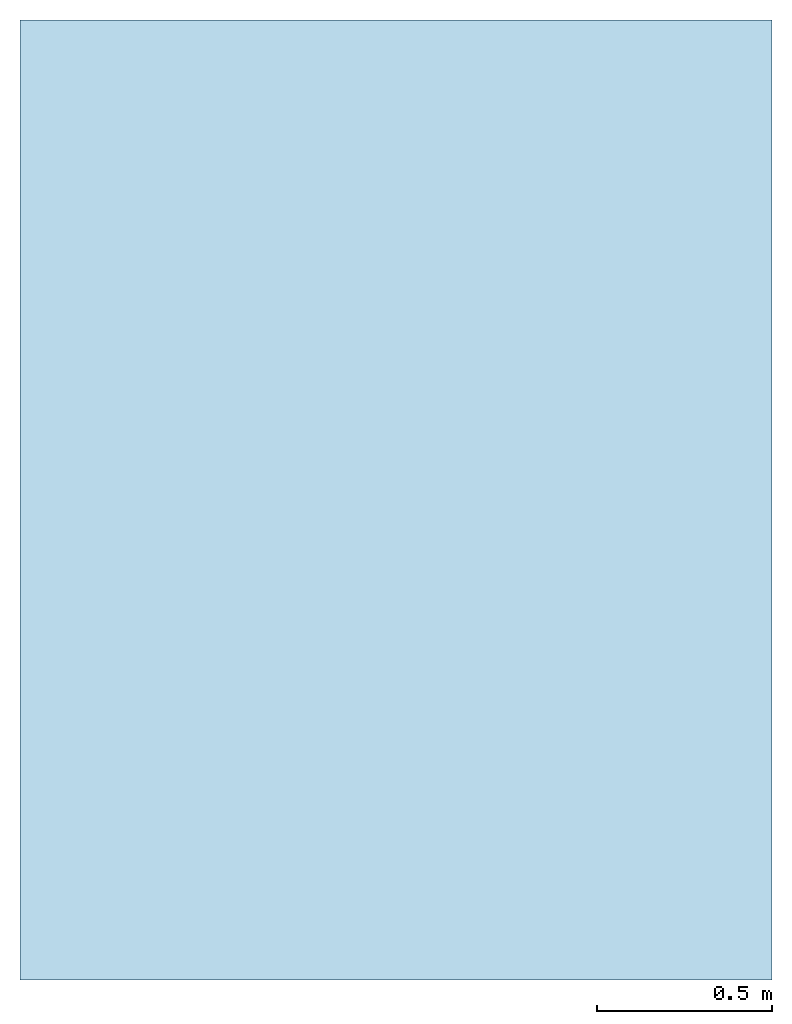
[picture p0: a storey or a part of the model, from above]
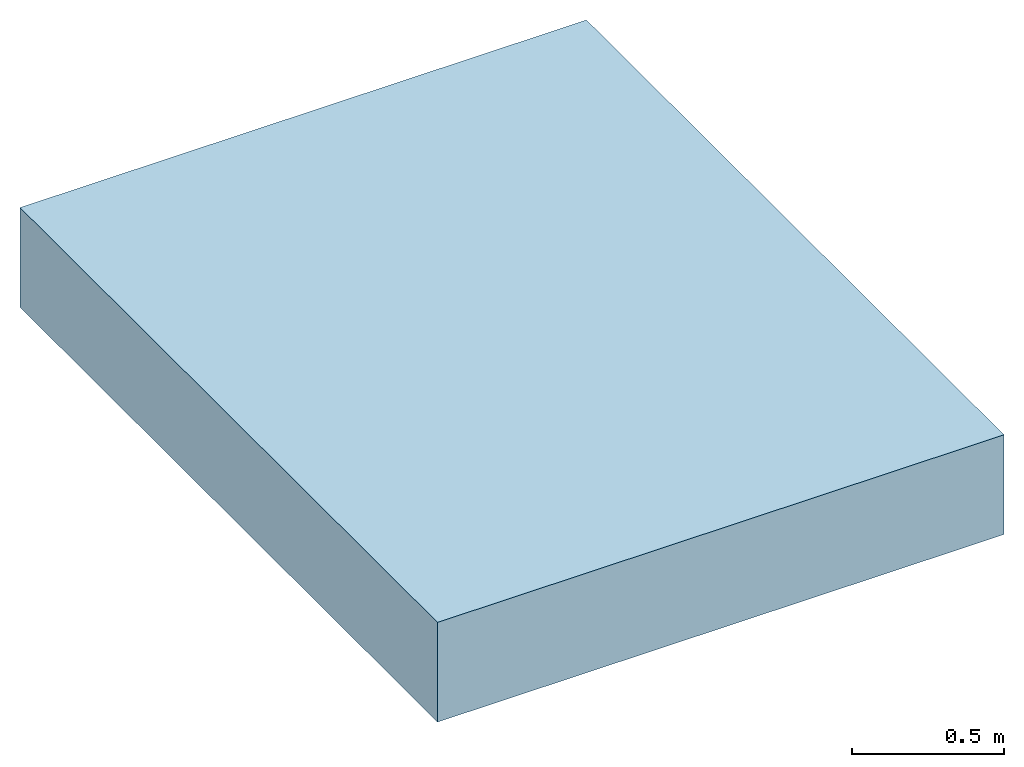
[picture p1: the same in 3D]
Properties of the parts of a building model (IFC2X3)

# File
Description: ViewDefinition [CoordinationView]
File name: 32301 - Junction channel - 500mm LG.ifc
Time: 2013-09-18T16:28:21
Written by: Autodesk Revit 2013
Made in: 20120221_2030(x64)

# IfcProject, Project Number
LongName: Project Name; Phase: Project Status

# IfcSite, Default
RefLatitude: 42, 21, 30, 344238; RefLongitude: -71, -3, -35, -194702; RefElevation: 0 mm

# IfcBuilding
Pset_BuildingCommon - NumberOfStoreys: 2
Other - Project Status: Project Status; Client Name: Owner; Project Address: Enter address here; Project Name: Project Name; Project Issue Date: Issue Date; Project Number: Project Number

# IfcBuildingStorey (2)
Graphics - Color: 0; Line Weight: 1; Symbol: M_Level Head - Circle: M_Level Head - Circle; Line Pattern: Center; Symbol at End 1 Default: no; Symbol at End 2 Default: yes
Constraints - Elevation Base: 0
Identity Data - Structural: no; Building Story: yes
Dimensions - Computation Height: 0 mm
Name | LongName = Name | Elevation (mm) = Constraints, Elevation (mm)
T.O. Fnd. Wall | T.O. Fnd. Wall | -300
Level 1 | Level 1 | 0

# IfcBuildingElementProxy: 32301 - Junction channel - 500mm LG, Civil-Drainage-Channel-ACO-KerbDrain-HB480(amar):32301 - Junction channel - 500mm LG:32301 - Junction channel - 500mm LG:481515
In: T.O. Fnd. Wall
Material: Acetal Resin, Black
Materials and Finishes - Channel Colour: Black; End Cap Material: N/A; Access Cover/Frame Finish: N/A; Channel Material: Vienite® Synthetic Resin Concrete; Access Cover/Frame Material: N/A; Access Cover/Frame Colour: N/A; Connection Pipe Material: N/A; Connection Pipe Material Colour: N/A; End Cap Colour: N/A
Dimensions - Junction Start: -5 mm; Void Width: 160 mm; Junction End: 155 mm; Void Length: 500 mm; Void Depth: -350 mm; Mitre Small End: 487 mm; junction void depth: 2000 mm; I/O endcap void depth: 2000 mm; Mitre Long end: 500 mm; Mitre Void End: 4570 mm; Mitre Void Start: 4565 mm; Straight Void Start: 0 mm; Void Start I/O: 0 mm; Void End I/O: 150 mm; Volume: 15887945 mm3
General - TagNumber: 0.000000; SerialNumber: 0.000000
Phasing - Phase Created: Phase 1
Constraints - Moves With Nearby Elements: no; Level: Level: Level 1
Pset_BuildingElementProxyCommon - Reference: 32301 - Junction channel - 500mm LG
Identity Data - Installation guidelines: http://www.aco.co.uk/download.php?id=120; Product Page URL: http://www.aco.co.uk/product_detail.php?id=3; Type Comments: ACO KerbDrain HB480 half battered junction channel unit 500mm long; Maintenance guidelines: http://www.aco.co.uk/download.php?id=120; Price: POA - contact ACO; Manufacturer: ACO Technologies plc - ACO Water Management Division; Address: ACO Business Park, Hitchin Road, Shefford, Bedfordshire, United Kingdom SG17 5TE; OmniClass Number: 23.70.50.24; Model: ACO KerbDrain HB480; URL: www.aco.co.uk; Telephone: +44 (0)1462 816666; Product brochure: http://www.aco.co.uk/download.php?id=120; Product Code: 32301; Assembly Description: Rain Water Drainage; Fax: +44 (0)1462 815895; Cost: 0; e-mail Technical: technical@aco.co.uk; OmniClass Title: Rainwater Removal; e-mail Sales: customersupport@aco.co.uk; Assembly Code: D2040; Model Description: Combined kerb and drainage system
Green Building Properties - Channel Recyclable: Fully recyclable; End Cap Recyclable: N/A; Access Cover/Frame Recyclable: N/A; Channel Recycled Material Content: 20% minimum; End Cap Recycled Material Content: N/A; Access Cover/Frame Recycled Material Content: N/A
Construction - Junction channel: yes; Bus stop kerb: no; LH inlet/outlet end cap: no; 25-11m internal mitre: no; HB480-500: no; RH inlet/outlet end cap: no; Access Unit: no; LH drop kerb: no; RH BS transition kerb: no; perforated centre stone: no; cable loop: no; Junction end cap: no; Centre Stone: no; Closing end cap: no; 25-11m external mitre: no; 10-8m external mitre: no; LH BS transition kerb: no; KDHB480 500_blindunit: no; 7-6m external mitre: no; RH drop kerb: no; Junction access unit: no
Data - Invert Depth: 325mm; Product Weight: 26 Kg; ACO Hydraulic Design Software: http://www.acodesign.co.uk; Channel C.S.A: 0.02m²; Product Dimensions: 500mm x 160mm x 350mm (LxWxH); Hydraulic Performance: http://www.aco.co.uk/download.php?id=120; Connection Pipe O.D: N/A; Product Standard: BS EN 1433:2002, CE marked, Kitemarked; Concrete Surround Volume - Load Class A 15 - D 400 - Concrete Pavement: N/A; Drainage Slot Intake area: 23268mm²/m; Load Class: A 15 - D 400; Drainage Slot Width: 15mm; Installation - Concrete Grade: Refer to brochure; Concrete Surround Volume - Load Class A 15 - D 400 - Grass or Asphalt Pavement: N/A
Other - Revision: 1; CreatedBy: www.aco.co.uk

# IfcOpeningElement: Opening (3)
In: Level 1
Dimensions - Thickness: 400 mm; Volume: 2332700000 mm3; Perimeter: 9790 mm; Area: 5901750 mm2
Phasing - Phase Created: Phase 1
Constraints - Related to Mass: no; Level: Level: Level 1; Room Bounding: yes; Height Offset From Level: 0 mm
Structural - Structural: no; Enable Analytical Model: no
Analytical Properties - Absorptance: 0.1; Heat Transfer Coefficient (U): 2.0925; Roughness: 1; Thermal Resistance (R): 0.477897; Thermal mass: 543920
Graphics - Coarse Scale Fill Color: 0
Construction - Function: 0; Default Thickness: 400 mm
Materials and Finishes - Structural Material: Earth

# IfcSlab: Floor:Generic Floor - 400mm, Floor:Generic Floor - 400mm:136426
In: Level 1
PredefinedType: FLOOR; Material: Earth 400 mm
Dimensions - Thickness: 400 mm; Volume: 2332700000 mm3; Perimeter: 9790 mm; Area: 5901750 mm2
Phasing - Phase Created: Phase 1
Constraints - Related to Mass: no; Level: Level: Level 1; Room Bounding: yes; Height Offset From Level: 0 mm
Structural - Structural: no; Enable Analytical Model: no
Pset_SlabCommon - Reference: Generic Floor - 400mm; IsExternal: no; LoadBearing: yes
Analytical Properties - Absorptance: 0.1; Heat Transfer Coefficient (U): 2.0925; Roughness: 1; Thermal Resistance (R): 0.477897; Thermal mass: 543920
Graphics - Coarse Scale Fill Color: 0
Construction - Function: 0; Default Thickness: 400 mm
Materials and Finishes - Structural Material: Earth
